VERSION 5.7 ;
  NOWIREEXTENSIONATPIN ON ;
  DIVIDERCHAR "/" ;
  BUSBITCHARS "[]" ;
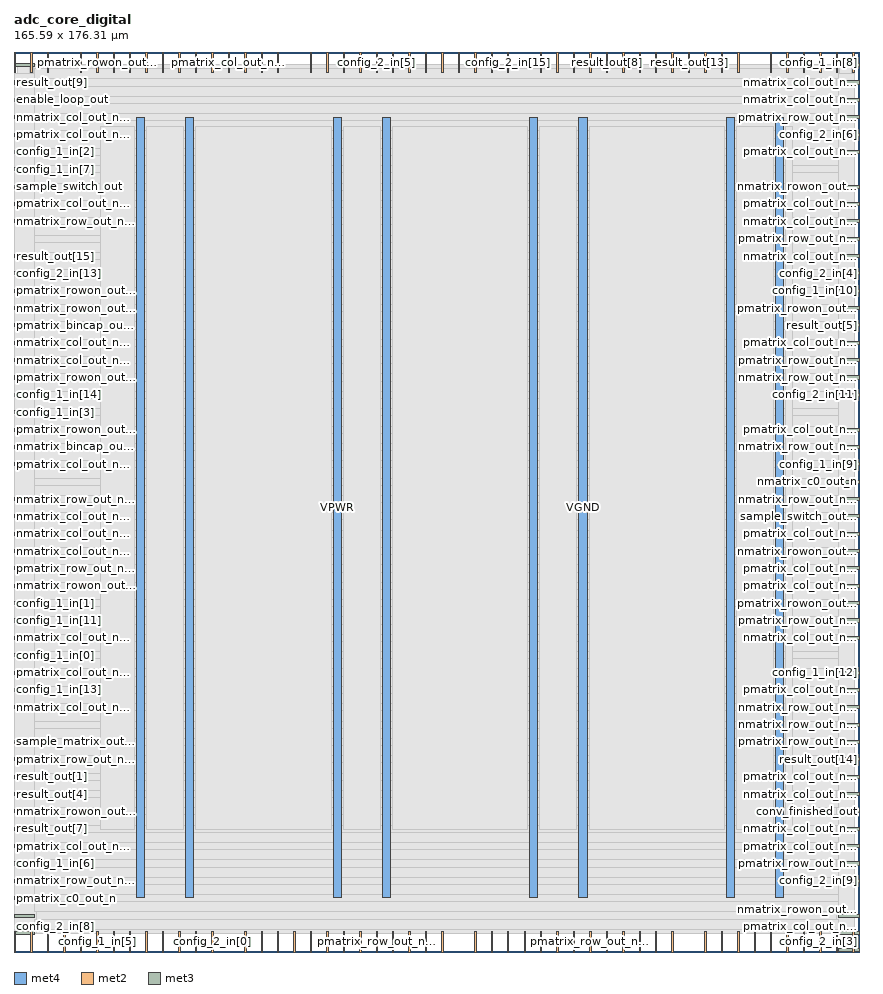
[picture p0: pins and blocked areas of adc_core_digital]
MACRO adc_core_digital
  CLASS BLOCK ;
  FOREIGN adc_core_digital ;
  ORIGIN 0.000 0.000 ;
  SIZE 165.590 BY 176.310 ;
  PIN VGND
    DIRECTION INOUT ;
    USE GROUND ;
    PORT
      LAYER met4 ;
        RECT 33.610 10.640 35.210 163.440 ;
    END
    PORT
      LAYER met4 ;
        RECT 72.135 10.640 73.735 163.440 ;
    END
    PORT
      LAYER met4 ;
        RECT 110.660 10.640 112.260 163.440 ;
    END
    PORT
      LAYER met4 ;
        RECT 149.185 10.640 150.785 163.440 ;
    END
  END VGND
  PIN VPWR
    DIRECTION INOUT ;
    USE POWER ;
    PORT
      LAYER met4 ;
        RECT 23.980 10.640 25.580 163.440 ;
    END
    PORT
      LAYER met4 ;
        RECT 62.505 10.640 64.105 163.440 ;
    END
    PORT
      LAYER met4 ;
        RECT 101.030 10.640 102.630 163.440 ;
    END
    PORT
      LAYER met4 ;
        RECT 139.555 10.640 141.155 163.440 ;
    END
  END VPWR
  PIN clk_dig_in
    DIRECTION INPUT ;
    USE SIGNAL ;
    PORT
      LAYER met2 ;
        RECT 135.330 172.310 135.610 176.310 ;
    END
  END clk_dig_in
  PIN comparator_in
    DIRECTION INPUT ;
    USE SIGNAL ;
    PORT
      LAYER met2 ;
        RECT 51.610 172.310 51.890 176.310 ;
    END
  END comparator_in
  PIN config_1_in[0]
    DIRECTION INPUT ;
    USE SIGNAL ;
    PORT
      LAYER met3 ;
        RECT 0.000 57.840 4.000 58.440 ;
    END
  END config_1_in[0]
  PIN config_1_in[10]
    DIRECTION INPUT ;
    USE SIGNAL ;
    PORT
      LAYER met3 ;
        RECT 161.590 129.240 165.590 129.840 ;
    END
  END config_1_in[10]
  PIN config_1_in[11]
    DIRECTION INPUT ;
    USE SIGNAL ;
    PORT
      LAYER met3 ;
        RECT 0.000 64.640 4.000 65.240 ;
    END
  END config_1_in[11]
  PIN config_1_in[12]
    DIRECTION INPUT ;
    USE SIGNAL ;
    PORT
      LAYER met3 ;
        RECT 161.590 54.440 165.590 55.040 ;
    END
  END config_1_in[12]
  PIN config_1_in[13]
    DIRECTION INPUT ;
    USE SIGNAL ;
    PORT
      LAYER met3 ;
        RECT 0.000 51.040 4.000 51.640 ;
    END
  END config_1_in[13]
  PIN config_1_in[14]
    DIRECTION INPUT ;
    USE SIGNAL ;
    PORT
      LAYER met3 ;
        RECT 0.000 108.840 4.000 109.440 ;
    END
  END config_1_in[14]
  PIN config_1_in[15]
    DIRECTION INPUT ;
    USE SIGNAL ;
    PORT
      LAYER met2 ;
        RECT 35.510 172.310 35.790 176.310 ;
    END
  END config_1_in[15]
  PIN config_1_in[1]
    DIRECTION INPUT ;
    USE SIGNAL ;
    PORT
      LAYER met3 ;
        RECT 0.000 68.040 4.000 68.640 ;
    END
  END config_1_in[1]
  PIN config_1_in[2]
    DIRECTION INPUT ;
    USE SIGNAL ;
    PORT
      LAYER met3 ;
        RECT 0.000 156.440 4.000 157.040 ;
    END
  END config_1_in[2]
  PIN config_1_in[3]
    DIRECTION INPUT ;
    USE SIGNAL ;
    PORT
      LAYER met3 ;
        RECT 0.000 105.440 4.000 106.040 ;
    END
  END config_1_in[3]
  PIN config_1_in[4]
    DIRECTION INPUT ;
    USE SIGNAL ;
    PORT
      LAYER met2 ;
        RECT 29.070 172.310 29.350 176.310 ;
    END
  END config_1_in[4]
  PIN config_1_in[5]
    DIRECTION INPUT ;
    USE SIGNAL ;
    PORT
      LAYER met2 ;
        RECT 16.190 0.000 16.470 4.000 ;
    END
  END config_1_in[5]
  PIN config_1_in[6]
    DIRECTION INPUT ;
    USE SIGNAL ;
    PORT
      LAYER met3 ;
        RECT 0.000 17.040 4.000 17.640 ;
    END
  END config_1_in[6]
  PIN config_1_in[7]
    DIRECTION INPUT ;
    USE SIGNAL ;
    PORT
      LAYER met3 ;
        RECT 0.000 153.040 4.000 153.640 ;
    END
  END config_1_in[7]
  PIN config_1_in[8]
    DIRECTION INPUT ;
    USE SIGNAL ;
    PORT
      LAYER met2 ;
        RECT 161.090 172.310 161.370 176.310 ;
    END
  END config_1_in[8]
  PIN config_1_in[9]
    DIRECTION INPUT ;
    USE SIGNAL ;
    PORT
      LAYER met3 ;
        RECT 161.590 95.240 165.590 95.840 ;
    END
  END config_1_in[9]
  PIN config_2_in[0]
    DIRECTION INPUT ;
    USE SIGNAL ;
    PORT
      LAYER met2 ;
        RECT 38.730 0.000 39.010 4.000 ;
    END
  END config_2_in[0]
  PIN config_2_in[10]
    DIRECTION INPUT ;
    USE SIGNAL ;
    PORT
      LAYER met2 ;
        RECT 67.710 172.310 67.990 176.310 ;
    END
  END config_2_in[10]
  PIN config_2_in[11]
    DIRECTION INPUT ;
    USE SIGNAL ;
    PORT
      LAYER met3 ;
        RECT 161.590 108.840 165.590 109.440 ;
    END
  END config_2_in[11]
  PIN config_2_in[12]
    DIRECTION INPUT ;
    USE SIGNAL ;
    PORT
      LAYER met3 ;
        RECT 161.590 0.040 165.590 0.640 ;
    END
  END config_2_in[12]
  PIN config_2_in[13]
    DIRECTION INPUT ;
    USE SIGNAL ;
    PORT
      LAYER met3 ;
        RECT 0.000 132.640 4.000 133.240 ;
    END
  END config_2_in[13]
  PIN config_2_in[14]
    DIRECTION INPUT ;
    USE SIGNAL ;
    PORT
      LAYER met2 ;
        RECT 54.830 0.000 55.110 4.000 ;
    END
  END config_2_in[14]
  PIN config_2_in[15]
    DIRECTION INPUT ;
    USE SIGNAL ;
    PORT
      LAYER met2 ;
        RECT 96.690 172.310 96.970 176.310 ;
    END
  END config_2_in[15]
  PIN config_2_in[1]
    DIRECTION INPUT ;
    USE SIGNAL ;
    PORT
      LAYER met2 ;
        RECT 109.570 0.000 109.850 4.000 ;
    END
  END config_2_in[1]
  PIN config_2_in[2]
    DIRECTION INPUT ;
    USE SIGNAL ;
    PORT
      LAYER met2 ;
        RECT 87.030 172.310 87.310 176.310 ;
    END
  END config_2_in[2]
  PIN config_2_in[3]
    DIRECTION INPUT ;
    USE SIGNAL ;
    PORT
      LAYER met2 ;
        RECT 157.870 0.000 158.150 4.000 ;
    END
  END config_2_in[3]
  PIN config_2_in[4]
    DIRECTION INPUT ;
    USE SIGNAL ;
    PORT
      LAYER met3 ;
        RECT 161.590 132.640 165.590 133.240 ;
    END
  END config_2_in[4]
  PIN config_2_in[5]
    DIRECTION INPUT ;
    USE SIGNAL ;
    PORT
      LAYER met2 ;
        RECT 70.930 172.310 71.210 176.310 ;
    END
  END config_2_in[5]
  PIN config_2_in[6]
    DIRECTION INPUT ;
    USE SIGNAL ;
    PORT
      LAYER met3 ;
        RECT 161.590 159.840 165.590 160.440 ;
    END
  END config_2_in[6]
  PIN config_2_in[7]
    DIRECTION INPUT ;
    USE SIGNAL ;
    PORT
      LAYER met2 ;
        RECT 138.550 172.310 138.830 176.310 ;
    END
  END config_2_in[7]
  PIN config_2_in[8]
    DIRECTION INPUT ;
    USE SIGNAL ;
    PORT
      LAYER met3 ;
        RECT 0.000 3.440 4.000 4.040 ;
    END
  END config_2_in[8]
  PIN config_2_in[9]
    DIRECTION INPUT ;
    USE SIGNAL ;
    PORT
      LAYER met3 ;
        RECT 161.590 13.640 165.590 14.240 ;
    END
  END config_2_in[9]
  PIN conv_finished_out
    DIRECTION OUTPUT TRISTATE ;
    USE SIGNAL ;
    PORT
      LAYER met3 ;
        RECT 161.590 27.240 165.590 27.840 ;
    END
  END conv_finished_out
  PIN enable_loop_out
    DIRECTION OUTPUT TRISTATE ;
    USE SIGNAL ;
    PORT
      LAYER met3 ;
        RECT 0.000 166.640 4.000 167.240 ;
    END
  END enable_loop_out
  PIN nmatrix_bincap_out_n[0]
    DIRECTION OUTPUT TRISTATE ;
    USE SIGNAL ;
    PORT
      LAYER met2 ;
        RECT 6.530 172.310 6.810 176.310 ;
    END
  END nmatrix_bincap_out_n[0]
  PIN nmatrix_bincap_out_n[1]
    DIRECTION OUTPUT TRISTATE ;
    USE SIGNAL ;
    PORT
      LAYER met3 ;
        RECT 0.000 98.640 4.000 99.240 ;
    END
  END nmatrix_bincap_out_n[1]
  PIN nmatrix_bincap_out_n[2]
    DIRECTION OUTPUT TRISTATE ;
    USE SIGNAL ;
    PORT
      LAYER met3 ;
        RECT 0.000 6.840 4.000 7.440 ;
    END
  END nmatrix_bincap_out_n[2]
  PIN nmatrix_c0_out_n
    DIRECTION OUTPUT TRISTATE ;
    USE SIGNAL ;
    PORT
      LAYER met3 ;
        RECT 161.590 91.840 165.590 92.440 ;
    END
  END nmatrix_c0_out_n
  PIN nmatrix_col_out_n[0]
    DIRECTION OUTPUT TRISTATE ;
    USE SIGNAL ;
    PORT
      LAYER met3 ;
        RECT 0.000 85.040 4.000 85.640 ;
    END
  END nmatrix_col_out_n[0]
  PIN nmatrix_col_out_n[10]
    DIRECTION OUTPUT TRISTATE ;
    USE SIGNAL ;
    PORT
      LAYER met3 ;
        RECT 0.000 173.440 4.000 174.040 ;
    END
  END nmatrix_col_out_n[10]
  PIN nmatrix_col_out_n[11]
    DIRECTION OUTPUT TRISTATE ;
    USE SIGNAL ;
    PORT
      LAYER met3 ;
        RECT 0.000 163.240 4.000 163.840 ;
    END
  END nmatrix_col_out_n[11]
  PIN nmatrix_col_out_n[12]
    DIRECTION OUTPUT TRISTATE ;
    USE SIGNAL ;
    PORT
      LAYER met2 ;
        RECT 151.430 0.000 151.710 4.000 ;
    END
  END nmatrix_col_out_n[12]
  PIN nmatrix_col_out_n[13]
    DIRECTION OUTPUT TRISTATE ;
    USE SIGNAL ;
    PORT
      LAYER met3 ;
        RECT 0.000 115.640 4.000 116.240 ;
    END
  END nmatrix_col_out_n[13]
  PIN nmatrix_col_out_n[14]
    DIRECTION OUTPUT TRISTATE ;
    USE SIGNAL ;
    PORT
      LAYER met2 ;
        RECT 148.210 172.310 148.490 176.310 ;
    END
  END nmatrix_col_out_n[14]
  PIN nmatrix_col_out_n[15]
    DIRECTION OUTPUT TRISTATE ;
    USE SIGNAL ;
    PORT
      LAYER met3 ;
        RECT 161.590 61.240 165.590 61.840 ;
    END
  END nmatrix_col_out_n[15]
  PIN nmatrix_col_out_n[16]
    DIRECTION OUTPUT TRISTATE ;
    USE SIGNAL ;
    PORT
      LAYER met3 ;
        RECT 0.000 119.040 4.000 119.640 ;
    END
  END nmatrix_col_out_n[16]
  PIN nmatrix_col_out_n[17]
    DIRECTION OUTPUT TRISTATE ;
    USE SIGNAL ;
    PORT
      LAYER met3 ;
        RECT 161.590 23.840 165.590 24.440 ;
    END
  END nmatrix_col_out_n[17]
  PIN nmatrix_col_out_n[18]
    DIRECTION OUTPUT TRISTATE ;
    USE SIGNAL ;
    PORT
      LAYER met2 ;
        RECT 48.390 0.000 48.670 4.000 ;
    END
  END nmatrix_col_out_n[18]
  PIN nmatrix_col_out_n[19]
    DIRECTION OUTPUT TRISTATE ;
    USE SIGNAL ;
    PORT
      LAYER met3 ;
        RECT 0.000 47.640 4.000 48.240 ;
    END
  END nmatrix_col_out_n[19]
  PIN nmatrix_col_out_n[1]
    DIRECTION OUTPUT TRISTATE ;
    USE SIGNAL ;
    PORT
      LAYER met3 ;
        RECT 0.000 61.240 4.000 61.840 ;
    END
  END nmatrix_col_out_n[1]
  PIN nmatrix_col_out_n[20]
    DIRECTION OUTPUT TRISTATE ;
    USE SIGNAL ;
    PORT
      LAYER met3 ;
        RECT 161.590 136.040 165.590 136.640 ;
    END
  END nmatrix_col_out_n[20]
  PIN nmatrix_col_out_n[21]
    DIRECTION OUTPUT TRISTATE ;
    USE SIGNAL ;
    PORT
      LAYER met2 ;
        RECT 48.390 172.310 48.670 176.310 ;
    END
  END nmatrix_col_out_n[21]
  PIN nmatrix_col_out_n[22]
    DIRECTION OUTPUT TRISTATE ;
    USE SIGNAL ;
    PORT
      LAYER met3 ;
        RECT 161.590 170.040 165.590 170.640 ;
    END
  END nmatrix_col_out_n[22]
  PIN nmatrix_col_out_n[23]
    DIRECTION OUTPUT TRISTATE ;
    USE SIGNAL ;
    PORT
      LAYER met3 ;
        RECT 0.000 81.640 4.000 82.240 ;
    END
  END nmatrix_col_out_n[23]
  PIN nmatrix_col_out_n[24]
    DIRECTION OUTPUT TRISTATE ;
    USE SIGNAL ;
    PORT
      LAYER met2 ;
        RECT 12.970 0.000 13.250 4.000 ;
    END
  END nmatrix_col_out_n[24]
  PIN nmatrix_col_out_n[25]
    DIRECTION OUTPUT TRISTATE ;
    USE SIGNAL ;
    PORT
      LAYER met3 ;
        RECT 0.000 78.240 4.000 78.840 ;
    END
  END nmatrix_col_out_n[25]
  PIN nmatrix_col_out_n[26]
    DIRECTION OUTPUT TRISTATE ;
    USE SIGNAL ;
    PORT
      LAYER met2 ;
        RECT 80.590 172.310 80.870 176.310 ;
    END
  END nmatrix_col_out_n[26]
  PIN nmatrix_col_out_n[27]
    DIRECTION OUTPUT TRISTATE ;
    USE SIGNAL ;
    PORT
      LAYER met3 ;
        RECT 161.590 142.840 165.590 143.440 ;
    END
  END nmatrix_col_out_n[27]
  PIN nmatrix_col_out_n[28]
    DIRECTION OUTPUT TRISTATE ;
    USE SIGNAL ;
    PORT
      LAYER met2 ;
        RECT 58.050 172.310 58.330 176.310 ;
    END
  END nmatrix_col_out_n[28]
  PIN nmatrix_col_out_n[29]
    DIRECTION OUTPUT TRISTATE ;
    USE SIGNAL ;
    PORT
      LAYER met3 ;
        RECT 161.590 166.640 165.590 167.240 ;
    END
  END nmatrix_col_out_n[29]
  PIN nmatrix_col_out_n[2]
    DIRECTION OUTPUT TRISTATE ;
    USE SIGNAL ;
    PORT
      LAYER met2 ;
        RECT 12.970 172.310 13.250 176.310 ;
    END
  END nmatrix_col_out_n[2]
  PIN nmatrix_col_out_n[30]
    DIRECTION OUTPUT TRISTATE ;
    USE SIGNAL ;
    PORT
      LAYER met2 ;
        RECT 128.890 0.000 129.170 4.000 ;
    END
  END nmatrix_col_out_n[30]
  PIN nmatrix_col_out_n[31]
    DIRECTION OUTPUT TRISTATE ;
    USE SIGNAL ;
    PORT
      LAYER met2 ;
        RECT 141.770 172.310 142.050 176.310 ;
    END
  END nmatrix_col_out_n[31]
  PIN nmatrix_col_out_n[3]
    DIRECTION OUTPUT TRISTATE ;
    USE SIGNAL ;
    PORT
      LAYER met2 ;
        RECT 25.850 172.310 26.130 176.310 ;
    END
  END nmatrix_col_out_n[3]
  PIN nmatrix_col_out_n[4]
    DIRECTION OUTPUT TRISTATE ;
    USE SIGNAL ;
    PORT
      LAYER met2 ;
        RECT 77.370 0.000 77.650 4.000 ;
    END
  END nmatrix_col_out_n[4]
  PIN nmatrix_col_out_n[5]
    DIRECTION OUTPUT TRISTATE ;
    USE SIGNAL ;
    PORT
      LAYER met2 ;
        RECT 135.330 0.000 135.610 4.000 ;
    END
  END nmatrix_col_out_n[5]
  PIN nmatrix_col_out_n[6]
    DIRECTION OUTPUT TRISTATE ;
    USE SIGNAL ;
    PORT
      LAYER met3 ;
        RECT 161.590 30.640 165.590 31.240 ;
    END
  END nmatrix_col_out_n[6]
  PIN nmatrix_col_out_n[7]
    DIRECTION OUTPUT TRISTATE ;
    USE SIGNAL ;
    PORT
      LAYER met2 ;
        RECT 125.670 0.000 125.950 4.000 ;
    END
  END nmatrix_col_out_n[7]
  PIN nmatrix_col_out_n[8]
    DIRECTION OUTPUT TRISTATE ;
    USE SIGNAL ;
    PORT
      LAYER met2 ;
        RECT 64.490 0.000 64.770 4.000 ;
    END
  END nmatrix_col_out_n[8]
  PIN nmatrix_col_out_n[9]
    DIRECTION OUTPUT TRISTATE ;
    USE SIGNAL ;
    PORT
      LAYER met3 ;
        RECT 161.590 173.440 165.590 174.040 ;
    END
  END nmatrix_col_out_n[9]
  PIN nmatrix_row_out_n[0]
    DIRECTION OUTPUT TRISTATE ;
    USE SIGNAL ;
    PORT
      LAYER met3 ;
        RECT 0.000 88.440 4.000 89.040 ;
    END
  END nmatrix_row_out_n[0]
  PIN nmatrix_row_out_n[10]
    DIRECTION OUTPUT TRISTATE ;
    USE SIGNAL ;
    PORT
      LAYER met3 ;
        RECT 161.590 47.640 165.590 48.240 ;
    END
  END nmatrix_row_out_n[10]
  PIN nmatrix_row_out_n[11]
    DIRECTION OUTPUT TRISTATE ;
    USE SIGNAL ;
    PORT
      LAYER met2 ;
        RECT 80.590 0.000 80.870 4.000 ;
    END
  END nmatrix_row_out_n[11]
  PIN nmatrix_row_out_n[12]
    DIRECTION OUTPUT TRISTATE ;
    USE SIGNAL ;
    PORT
      LAYER met3 ;
        RECT 161.590 88.440 165.590 89.040 ;
    END
  END nmatrix_row_out_n[12]
  PIN nmatrix_row_out_n[13]
    DIRECTION OUTPUT TRISTATE ;
    USE SIGNAL ;
    PORT
      LAYER met2 ;
        RECT 125.670 172.310 125.950 176.310 ;
    END
  END nmatrix_row_out_n[13]
  PIN nmatrix_row_out_n[14]
    DIRECTION OUTPUT TRISTATE ;
    USE SIGNAL ;
    PORT
      LAYER met2 ;
        RECT 45.170 172.310 45.450 176.310 ;
    END
  END nmatrix_row_out_n[14]
  PIN nmatrix_row_out_n[15]
    DIRECTION OUTPUT TRISTATE ;
    USE SIGNAL ;
    PORT
      LAYER met2 ;
        RECT 51.610 0.000 51.890 4.000 ;
    END
  END nmatrix_row_out_n[15]
  PIN nmatrix_row_out_n[1]
    DIRECTION OUTPUT TRISTATE ;
    USE SIGNAL ;
    PORT
      LAYER met3 ;
        RECT 0.000 142.840 4.000 143.440 ;
    END
  END nmatrix_row_out_n[1]
  PIN nmatrix_row_out_n[2]
    DIRECTION OUTPUT TRISTATE ;
    USE SIGNAL ;
    PORT
      LAYER met2 ;
        RECT 22.630 0.000 22.910 4.000 ;
    END
  END nmatrix_row_out_n[2]
  PIN nmatrix_row_out_n[3]
    DIRECTION OUTPUT TRISTATE ;
    USE SIGNAL ;
    PORT
      LAYER met2 ;
        RECT 90.250 0.000 90.530 4.000 ;
    END
  END nmatrix_row_out_n[3]
  PIN nmatrix_row_out_n[4]
    DIRECTION OUTPUT TRISTATE ;
    USE SIGNAL ;
    PORT
      LAYER met3 ;
        RECT 161.590 98.640 165.590 99.240 ;
    END
  END nmatrix_row_out_n[4]
  PIN nmatrix_row_out_n[5]
    DIRECTION OUTPUT TRISTATE ;
    USE SIGNAL ;
    PORT
      LAYER met3 ;
        RECT 161.590 44.240 165.590 44.840 ;
    END
  END nmatrix_row_out_n[5]
  PIN nmatrix_row_out_n[6]
    DIRECTION OUTPUT TRISTATE ;
    USE SIGNAL ;
    PORT
      LAYER met2 ;
        RECT 106.350 172.310 106.630 176.310 ;
    END
  END nmatrix_row_out_n[6]
  PIN nmatrix_row_out_n[7]
    DIRECTION OUTPUT TRISTATE ;
    USE SIGNAL ;
    PORT
      LAYER met3 ;
        RECT 161.590 112.240 165.590 112.840 ;
    END
  END nmatrix_row_out_n[7]
  PIN nmatrix_row_out_n[8]
    DIRECTION OUTPUT TRISTATE ;
    USE SIGNAL ;
    PORT
      LAYER met2 ;
        RECT 122.450 172.310 122.730 176.310 ;
    END
  END nmatrix_row_out_n[8]
  PIN nmatrix_row_out_n[9]
    DIRECTION OUTPUT TRISTATE ;
    USE SIGNAL ;
    PORT
      LAYER met3 ;
        RECT 0.000 13.640 4.000 14.240 ;
    END
  END nmatrix_row_out_n[9]
  PIN nmatrix_rowon_out_n[0]
    DIRECTION OUTPUT TRISTATE ;
    USE SIGNAL ;
    PORT
      LAYER met3 ;
        RECT 0.000 125.840 4.000 126.440 ;
    END
  END nmatrix_rowon_out_n[0]
  PIN nmatrix_rowon_out_n[10]
    DIRECTION OUTPUT TRISTATE ;
    USE SIGNAL ;
    PORT
      LAYER met2 ;
        RECT 138.550 0.000 138.830 4.000 ;
    END
  END nmatrix_rowon_out_n[10]
  PIN nmatrix_rowon_out_n[11]
    DIRECTION OUTPUT TRISTATE ;
    USE SIGNAL ;
    PORT
      LAYER met3 ;
        RECT 161.590 78.240 165.590 78.840 ;
    END
  END nmatrix_rowon_out_n[11]
  PIN nmatrix_rowon_out_n[12]
    DIRECTION OUTPUT TRISTATE ;
    USE SIGNAL ;
    PORT
      LAYER met2 ;
        RECT 151.430 172.310 151.710 176.310 ;
    END
  END nmatrix_rowon_out_n[12]
  PIN nmatrix_rowon_out_n[13]
    DIRECTION OUTPUT TRISTATE ;
    USE SIGNAL ;
    PORT
      LAYER met3 ;
        RECT 161.590 149.640 165.590 150.240 ;
    END
  END nmatrix_rowon_out_n[13]
  PIN nmatrix_rowon_out_n[14]
    DIRECTION OUTPUT TRISTATE ;
    USE SIGNAL ;
    PORT
      LAYER met2 ;
        RECT 6.530 0.000 6.810 4.000 ;
    END
  END nmatrix_rowon_out_n[14]
  PIN nmatrix_rowon_out_n[15]
    DIRECTION OUTPUT TRISTATE ;
    USE SIGNAL ;
    PORT
      LAYER met2 ;
        RECT 58.050 0.000 58.330 4.000 ;
    END
  END nmatrix_rowon_out_n[15]
  PIN nmatrix_rowon_out_n[1]
    DIRECTION OUTPUT TRISTATE ;
    USE SIGNAL ;
    PORT
      LAYER met2 ;
        RECT 119.230 172.310 119.510 176.310 ;
    END
  END nmatrix_rowon_out_n[1]
  PIN nmatrix_rowon_out_n[2]
    DIRECTION OUTPUT TRISTATE ;
    USE SIGNAL ;
    PORT
      LAYER met2 ;
        RECT 19.410 172.310 19.690 176.310 ;
    END
  END nmatrix_rowon_out_n[2]
  PIN nmatrix_rowon_out_n[3]
    DIRECTION OUTPUT TRISTATE ;
    USE SIGNAL ;
    PORT
      LAYER met2 ;
        RECT 67.710 0.000 67.990 4.000 ;
    END
  END nmatrix_rowon_out_n[3]
  PIN nmatrix_rowon_out_n[4]
    DIRECTION OUTPUT TRISTATE ;
    USE SIGNAL ;
    PORT
      LAYER met3 ;
        RECT 161.590 6.840 165.590 7.440 ;
    END
  END nmatrix_rowon_out_n[4]
  PIN nmatrix_rowon_out_n[5]
    DIRECTION OUTPUT TRISTATE ;
    USE SIGNAL ;
    PORT
      LAYER met2 ;
        RECT 144.990 0.000 145.270 4.000 ;
    END
  END nmatrix_rowon_out_n[5]
  PIN nmatrix_rowon_out_n[6]
    DIRECTION OUTPUT TRISTATE ;
    USE SIGNAL ;
    PORT
      LAYER met2 ;
        RECT 106.350 0.000 106.630 4.000 ;
    END
  END nmatrix_rowon_out_n[6]
  PIN nmatrix_rowon_out_n[7]
    DIRECTION OUTPUT TRISTATE ;
    USE SIGNAL ;
    PORT
      LAYER met3 ;
        RECT 0.000 71.440 4.000 72.040 ;
    END
  END nmatrix_rowon_out_n[7]
  PIN nmatrix_rowon_out_n[8]
    DIRECTION OUTPUT TRISTATE ;
    USE SIGNAL ;
    PORT
      LAYER met3 ;
        RECT 0.000 27.240 4.000 27.840 ;
    END
  END nmatrix_rowon_out_n[8]
  PIN nmatrix_rowon_out_n[9]
    DIRECTION OUTPUT TRISTATE ;
    USE SIGNAL ;
    PORT
      LAYER met2 ;
        RECT 128.890 172.310 129.170 176.310 ;
    END
  END nmatrix_rowon_out_n[9]
  PIN pmatrix_bincap_out_n[0]
    DIRECTION OUTPUT TRISTATE ;
    USE SIGNAL ;
    PORT
      LAYER met2 ;
        RECT 38.730 172.310 39.010 176.310 ;
    END
  END pmatrix_bincap_out_n[0]
  PIN pmatrix_bincap_out_n[1]
    DIRECTION OUTPUT TRISTATE ;
    USE SIGNAL ;
    PORT
      LAYER met2 ;
        RECT 141.770 0.000 142.050 4.000 ;
    END
  END pmatrix_bincap_out_n[1]
  PIN pmatrix_bincap_out_n[2]
    DIRECTION OUTPUT TRISTATE ;
    USE SIGNAL ;
    PORT
      LAYER met3 ;
        RECT 0.000 122.440 4.000 123.040 ;
    END
  END pmatrix_bincap_out_n[2]
  PIN pmatrix_c0_out_n
    DIRECTION OUTPUT TRISTATE ;
    USE SIGNAL ;
    PORT
      LAYER met3 ;
        RECT 0.000 10.240 4.000 10.840 ;
    END
  END pmatrix_c0_out_n
  PIN pmatrix_col_out_n[0]
    DIRECTION OUTPUT TRISTATE ;
    USE SIGNAL ;
    PORT
      LAYER met3 ;
        RECT 0.000 54.440 4.000 55.040 ;
    END
  END pmatrix_col_out_n[0]
  PIN pmatrix_col_out_n[10]
    DIRECTION OUTPUT TRISTATE ;
    USE SIGNAL ;
    PORT
      LAYER met3 ;
        RECT 161.590 156.440 165.590 157.040 ;
    END
  END pmatrix_col_out_n[10]
  PIN pmatrix_col_out_n[11]
    DIRECTION OUTPUT TRISTATE ;
    USE SIGNAL ;
    PORT
      LAYER met3 ;
        RECT 161.590 20.440 165.590 21.040 ;
    END
  END pmatrix_col_out_n[11]
  PIN pmatrix_col_out_n[12]
    DIRECTION OUTPUT TRISTATE ;
    USE SIGNAL ;
    PORT
      LAYER met3 ;
        RECT 161.590 71.440 165.590 72.040 ;
    END
  END pmatrix_col_out_n[12]
  PIN pmatrix_col_out_n[13]
    DIRECTION OUTPUT TRISTATE ;
    USE SIGNAL ;
    PORT
      LAYER met2 ;
        RECT 3.310 172.310 3.590 176.310 ;
    END
  END pmatrix_col_out_n[13]
  PIN pmatrix_col_out_n[14]
    DIRECTION OUTPUT TRISTATE ;
    USE SIGNAL ;
    PORT
      LAYER met3 ;
        RECT 161.590 102.040 165.590 102.640 ;
    END
  END pmatrix_col_out_n[14]
  PIN pmatrix_col_out_n[15]
    DIRECTION OUTPUT TRISTATE ;
    USE SIGNAL ;
    PORT
      LAYER met3 ;
        RECT 161.590 3.440 165.590 4.040 ;
    END
  END pmatrix_col_out_n[15]
  PIN pmatrix_col_out_n[16]
    DIRECTION OUTPUT TRISTATE ;
    USE SIGNAL ;
    PORT
      LAYER met2 ;
        RECT 93.470 172.310 93.750 176.310 ;
    END
  END pmatrix_col_out_n[16]
  PIN pmatrix_col_out_n[17]
    DIRECTION OUTPUT TRISTATE ;
    USE SIGNAL ;
    PORT
      LAYER met2 ;
        RECT 41.950 172.310 42.230 176.310 ;
    END
  END pmatrix_col_out_n[17]
  PIN pmatrix_col_out_n[18]
    DIRECTION OUTPUT TRISTATE ;
    USE SIGNAL ;
    PORT
      LAYER met2 ;
        RECT 93.470 0.000 93.750 4.000 ;
    END
  END pmatrix_col_out_n[18]
  PIN pmatrix_col_out_n[19]
    DIRECTION OUTPUT TRISTATE ;
    USE SIGNAL ;
    PORT
      LAYER met2 ;
        RECT 35.510 0.000 35.790 4.000 ;
    END
  END pmatrix_col_out_n[19]
  PIN pmatrix_col_out_n[1]
    DIRECTION OUTPUT TRISTATE ;
    USE SIGNAL ;
    PORT
      LAYER met2 ;
        RECT 61.270 172.310 61.550 176.310 ;
    END
  END pmatrix_col_out_n[1]
  PIN pmatrix_col_out_n[20]
    DIRECTION OUTPUT TRISTATE ;
    USE SIGNAL ;
    PORT
      LAYER met2 ;
        RECT 122.450 0.000 122.730 4.000 ;
    END
  END pmatrix_col_out_n[20]
  PIN pmatrix_col_out_n[21]
    DIRECTION OUTPUT TRISTATE ;
    USE SIGNAL ;
    PORT
      LAYER met2 ;
        RECT 161.090 0.000 161.370 4.000 ;
    END
  END pmatrix_col_out_n[21]
  PIN pmatrix_col_out_n[22]
    DIRECTION OUTPUT TRISTATE ;
    USE SIGNAL ;
    PORT
      LAYER met2 ;
        RECT 157.870 172.310 158.150 176.310 ;
    END
  END pmatrix_col_out_n[22]
  PIN pmatrix_col_out_n[23]
    DIRECTION OUTPUT TRISTATE ;
    USE SIGNAL ;
    PORT
      LAYER met3 ;
        RECT 161.590 74.840 165.590 75.440 ;
    END
  END pmatrix_col_out_n[23]
  PIN pmatrix_col_out_n[24]
    DIRECTION OUTPUT TRISTATE ;
    USE SIGNAL ;
    PORT
      LAYER met2 ;
        RECT 64.490 172.310 64.770 176.310 ;
    END
  END pmatrix_col_out_n[24]
  PIN pmatrix_col_out_n[25]
    DIRECTION OUTPUT TRISTATE ;
    USE SIGNAL ;
    PORT
      LAYER met2 ;
        RECT 90.250 172.310 90.530 176.310 ;
    END
  END pmatrix_col_out_n[25]
  PIN pmatrix_col_out_n[26]
    DIRECTION OUTPUT TRISTATE ;
    USE SIGNAL ;
    PORT
      LAYER met2 ;
        RECT 83.810 172.310 84.090 176.310 ;
    END
  END pmatrix_col_out_n[26]
  PIN pmatrix_col_out_n[27]
    DIRECTION OUTPUT TRISTATE ;
    USE SIGNAL ;
    PORT
      LAYER met3 ;
        RECT 0.000 95.240 4.000 95.840 ;
    END
  END pmatrix_col_out_n[27]
  PIN pmatrix_col_out_n[28]
    DIRECTION OUTPUT TRISTATE ;
    USE SIGNAL ;
    PORT
      LAYER met2 ;
        RECT 25.850 0.000 26.130 4.000 ;
    END
  END pmatrix_col_out_n[28]
  PIN pmatrix_col_out_n[29]
    DIRECTION OUTPUT TRISTATE ;
    USE SIGNAL ;
    PORT
      LAYER met3 ;
        RECT 161.590 34.040 165.590 34.640 ;
    END
  END pmatrix_col_out_n[29]
  PIN pmatrix_col_out_n[2]
    DIRECTION OUTPUT TRISTATE ;
    USE SIGNAL ;
    PORT
      LAYER met2 ;
        RECT 74.150 0.000 74.430 4.000 ;
    END
  END pmatrix_col_out_n[2]
  PIN pmatrix_col_out_n[30]
    DIRECTION OUTPUT TRISTATE ;
    USE SIGNAL ;
    PORT
      LAYER met3 ;
        RECT 161.590 146.240 165.590 146.840 ;
    END
  END pmatrix_col_out_n[30]
  PIN pmatrix_col_out_n[31]
    DIRECTION OUTPUT TRISTATE ;
    USE SIGNAL ;
    PORT
      LAYER met3 ;
        RECT 0.000 146.240 4.000 146.840 ;
    END
  END pmatrix_col_out_n[31]
  PIN pmatrix_col_out_n[3]
    DIRECTION OUTPUT TRISTATE ;
    USE SIGNAL ;
    PORT
      LAYER met2 ;
        RECT 103.130 172.310 103.410 176.310 ;
    END
  END pmatrix_col_out_n[3]
  PIN pmatrix_col_out_n[4]
    DIRECTION OUTPUT TRISTATE ;
    USE SIGNAL ;
    PORT
      LAYER met3 ;
        RECT 0.000 159.840 4.000 160.440 ;
    END
  END pmatrix_col_out_n[4]
  PIN pmatrix_col_out_n[5]
    DIRECTION OUTPUT TRISTATE ;
    USE SIGNAL ;
    PORT
      LAYER met3 ;
        RECT 161.590 51.040 165.590 51.640 ;
    END
  END pmatrix_col_out_n[5]
  PIN pmatrix_col_out_n[6]
    DIRECTION OUTPUT TRISTATE ;
    USE SIGNAL ;
    PORT
      LAYER met3 ;
        RECT 161.590 119.040 165.590 119.640 ;
    END
  END pmatrix_col_out_n[6]
  PIN pmatrix_col_out_n[7]
    DIRECTION OUTPUT TRISTATE ;
    USE SIGNAL ;
    PORT
      LAYER met2 ;
        RECT 32.290 172.310 32.570 176.310 ;
    END
  END pmatrix_col_out_n[7]
  PIN pmatrix_col_out_n[8]
    DIRECTION OUTPUT TRISTATE ;
    USE SIGNAL ;
    PORT
      LAYER met3 ;
        RECT 161.590 81.640 165.590 82.240 ;
    END
  END pmatrix_col_out_n[8]
  PIN pmatrix_col_out_n[9]
    DIRECTION OUTPUT TRISTATE ;
    USE SIGNAL ;
    PORT
      LAYER met3 ;
        RECT 0.000 20.440 4.000 21.040 ;
    END
  END pmatrix_col_out_n[9]
  PIN pmatrix_row_out_n[0]
    DIRECTION OUTPUT TRISTATE ;
    USE SIGNAL ;
    PORT
      LAYER met3 ;
        RECT 0.000 37.440 4.000 38.040 ;
    END
  END pmatrix_row_out_n[0]
  PIN pmatrix_row_out_n[10]
    DIRECTION OUTPUT TRISTATE ;
    USE SIGNAL ;
    PORT
      LAYER met3 ;
        RECT 161.590 139.440 165.590 140.040 ;
    END
  END pmatrix_row_out_n[10]
  PIN pmatrix_row_out_n[11]
    DIRECTION OUTPUT TRISTATE ;
    USE SIGNAL ;
    PORT
      LAYER met2 ;
        RECT 112.790 172.310 113.070 176.310 ;
    END
  END pmatrix_row_out_n[11]
  PIN pmatrix_row_out_n[12]
    DIRECTION OUTPUT TRISTATE ;
    USE SIGNAL ;
    PORT
      LAYER met2 ;
        RECT 45.170 0.000 45.450 4.000 ;
    END
  END pmatrix_row_out_n[12]
  PIN pmatrix_row_out_n[13]
    DIRECTION OUTPUT TRISTATE ;
    USE SIGNAL ;
    PORT
      LAYER met3 ;
        RECT 161.590 64.640 165.590 65.240 ;
    END
  END pmatrix_row_out_n[13]
  PIN pmatrix_row_out_n[14]
    DIRECTION OUTPUT TRISTATE ;
    USE SIGNAL ;
    PORT
      LAYER met2 ;
        RECT 112.790 0.000 113.070 4.000 ;
    END
  END pmatrix_row_out_n[14]
  PIN pmatrix_row_out_n[15]
    DIRECTION OUTPUT TRISTATE ;
    USE SIGNAL ;
    PORT
      LAYER met3 ;
        RECT 161.590 17.040 165.590 17.640 ;
    END
  END pmatrix_row_out_n[15]
  PIN pmatrix_row_out_n[1]
    DIRECTION OUTPUT TRISTATE ;
    USE SIGNAL ;
    PORT
      LAYER met2 ;
        RECT 0.090 172.310 0.370 176.310 ;
    END
  END pmatrix_row_out_n[1]
  PIN pmatrix_row_out_n[2]
    DIRECTION OUTPUT TRISTATE ;
    USE SIGNAL ;
    PORT
      LAYER met2 ;
        RECT 148.210 0.000 148.490 4.000 ;
    END
  END pmatrix_row_out_n[2]
  PIN pmatrix_row_out_n[3]
    DIRECTION OUTPUT TRISTATE ;
    USE SIGNAL ;
    PORT
      LAYER met2 ;
        RECT 19.410 0.000 19.690 4.000 ;
    END
  END pmatrix_row_out_n[3]
  PIN pmatrix_row_out_n[4]
    DIRECTION OUTPUT TRISTATE ;
    USE SIGNAL ;
    PORT
      LAYER met2 ;
        RECT 70.930 0.000 71.210 4.000 ;
    END
  END pmatrix_row_out_n[4]
  PIN pmatrix_row_out_n[5]
    DIRECTION OUTPUT TRISTATE ;
    USE SIGNAL ;
    PORT
      LAYER met3 ;
        RECT 161.590 40.840 165.590 41.440 ;
    END
  END pmatrix_row_out_n[5]
  PIN pmatrix_row_out_n[6]
    DIRECTION OUTPUT TRISTATE ;
    USE SIGNAL ;
    PORT
      LAYER met3 ;
        RECT 161.590 163.240 165.590 163.840 ;
    END
  END pmatrix_row_out_n[6]
  PIN pmatrix_row_out_n[7]
    DIRECTION OUTPUT TRISTATE ;
    USE SIGNAL ;
    PORT
      LAYER met3 ;
        RECT 161.590 115.640 165.590 116.240 ;
    END
  END pmatrix_row_out_n[7]
  PIN pmatrix_row_out_n[8]
    DIRECTION OUTPUT TRISTATE ;
    USE SIGNAL ;
    PORT
      LAYER met2 ;
        RECT 154.650 0.000 154.930 4.000 ;
    END
  END pmatrix_row_out_n[8]
  PIN pmatrix_row_out_n[9]
    DIRECTION OUTPUT TRISTATE ;
    USE SIGNAL ;
    PORT
      LAYER met3 ;
        RECT 0.000 74.840 4.000 75.440 ;
    END
  END pmatrix_row_out_n[9]
  PIN pmatrix_rowon_out_n[0]
    DIRECTION OUTPUT TRISTATE ;
    USE SIGNAL ;
    PORT
      LAYER met3 ;
        RECT 161.590 68.040 165.590 68.640 ;
    END
  END pmatrix_rowon_out_n[0]
  PIN pmatrix_rowon_out_n[10]
    DIRECTION OUTPUT TRISTATE ;
    USE SIGNAL ;
    PORT
      LAYER met2 ;
        RECT 3.310 0.000 3.590 4.000 ;
    END
  END pmatrix_rowon_out_n[10]
  PIN pmatrix_rowon_out_n[11]
    DIRECTION OUTPUT TRISTATE ;
    USE SIGNAL ;
    PORT
      LAYER met3 ;
        RECT 161.590 125.840 165.590 126.440 ;
    END
  END pmatrix_rowon_out_n[11]
  PIN pmatrix_rowon_out_n[12]
    DIRECTION OUTPUT TRISTATE ;
    USE SIGNAL ;
    PORT
      LAYER met2 ;
        RECT 164.310 172.310 164.590 176.310 ;
    END
  END pmatrix_rowon_out_n[12]
  PIN pmatrix_rowon_out_n[13]
    DIRECTION OUTPUT TRISTATE ;
    USE SIGNAL ;
    PORT
      LAYER met2 ;
        RECT 164.310 0.000 164.590 4.000 ;
    END
  END pmatrix_rowon_out_n[13]
  PIN pmatrix_rowon_out_n[14]
    DIRECTION OUTPUT TRISTATE ;
    USE SIGNAL ;
    PORT
      LAYER met2 ;
        RECT 154.650 172.310 154.930 176.310 ;
    END
  END pmatrix_rowon_out_n[14]
  PIN pmatrix_rowon_out_n[15]
    DIRECTION OUTPUT TRISTATE ;
    USE SIGNAL ;
    PORT
      LAYER met2 ;
        RECT 99.910 0.000 100.190 4.000 ;
    END
  END pmatrix_rowon_out_n[15]
  PIN pmatrix_rowon_out_n[1]
    DIRECTION OUTPUT TRISTATE ;
    USE SIGNAL ;
    PORT
      LAYER met3 ;
        RECT 0.000 112.240 4.000 112.840 ;
    END
  END pmatrix_rowon_out_n[1]
  PIN pmatrix_rowon_out_n[2]
    DIRECTION OUTPUT TRISTATE ;
    USE SIGNAL ;
    PORT
      LAYER met2 ;
        RECT 103.130 0.000 103.410 4.000 ;
    END
  END pmatrix_rowon_out_n[2]
  PIN pmatrix_rowon_out_n[3]
    DIRECTION OUTPUT TRISTATE ;
    USE SIGNAL ;
    PORT
      LAYER met2 ;
        RECT 0.090 0.000 0.370 4.000 ;
    END
  END pmatrix_rowon_out_n[3]
  PIN pmatrix_rowon_out_n[4]
    DIRECTION OUTPUT TRISTATE ;
    USE SIGNAL ;
    PORT
      LAYER met2 ;
        RECT 119.230 0.000 119.510 4.000 ;
    END
  END pmatrix_rowon_out_n[4]
  PIN pmatrix_rowon_out_n[5]
    DIRECTION OUTPUT TRISTATE ;
    USE SIGNAL ;
    PORT
      LAYER met3 ;
        RECT 0.000 129.240 4.000 129.840 ;
    END
  END pmatrix_rowon_out_n[5]
  PIN pmatrix_rowon_out_n[6]
    DIRECTION OUTPUT TRISTATE ;
    USE SIGNAL ;
    PORT
      LAYER met2 ;
        RECT 16.190 172.310 16.470 176.310 ;
    END
  END pmatrix_rowon_out_n[6]
  PIN pmatrix_rowon_out_n[7]
    DIRECTION OUTPUT TRISTATE ;
    USE SIGNAL ;
    PORT
      LAYER met2 ;
        RECT 77.370 172.310 77.650 176.310 ;
    END
  END pmatrix_rowon_out_n[7]
  PIN pmatrix_rowon_out_n[8]
    DIRECTION OUTPUT TRISTATE ;
    USE SIGNAL ;
    PORT
      LAYER met3 ;
        RECT 0.000 102.040 4.000 102.640 ;
    END
  END pmatrix_rowon_out_n[8]
  PIN pmatrix_rowon_out_n[9]
    DIRECTION OUTPUT TRISTATE ;
    USE SIGNAL ;
    PORT
      LAYER met2 ;
        RECT 29.070 0.000 29.350 4.000 ;
    END
  END pmatrix_rowon_out_n[9]
  PIN result_out[0]
    DIRECTION OUTPUT TRISTATE ;
    USE SIGNAL ;
    PORT
      LAYER met2 ;
        RECT 9.750 0.000 10.030 4.000 ;
    END
  END result_out[0]
  PIN result_out[10]
    DIRECTION OUTPUT TRISTATE ;
    USE SIGNAL ;
    PORT
      LAYER met2 ;
        RECT 109.570 172.310 109.850 176.310 ;
    END
  END result_out[10]
  PIN result_out[11]
    DIRECTION OUTPUT TRISTATE ;
    USE SIGNAL ;
    PORT
      LAYER met2 ;
        RECT 74.150 172.310 74.430 176.310 ;
    END
  END result_out[11]
  PIN result_out[12]
    DIRECTION OUTPUT TRISTATE ;
    USE SIGNAL ;
    PORT
      LAYER met2 ;
        RECT 83.810 0.000 84.090 4.000 ;
    END
  END result_out[12]
  PIN result_out[13]
    DIRECTION OUTPUT TRISTATE ;
    USE SIGNAL ;
    PORT
      LAYER met2 ;
        RECT 132.110 172.310 132.390 176.310 ;
    END
  END result_out[13]
  PIN result_out[14]
    DIRECTION OUTPUT TRISTATE ;
    USE SIGNAL ;
    PORT
      LAYER met3 ;
        RECT 161.590 37.440 165.590 38.040 ;
    END
  END result_out[14]
  PIN result_out[15]
    DIRECTION OUTPUT TRISTATE ;
    USE SIGNAL ;
    PORT
      LAYER met3 ;
        RECT 0.000 136.040 4.000 136.640 ;
    END
  END result_out[15]
  PIN result_out[1]
    DIRECTION OUTPUT TRISTATE ;
    USE SIGNAL ;
    PORT
      LAYER met3 ;
        RECT 0.000 34.040 4.000 34.640 ;
    END
  END result_out[1]
  PIN result_out[2]
    DIRECTION OUTPUT TRISTATE ;
    USE SIGNAL ;
    PORT
      LAYER met2 ;
        RECT 32.290 0.000 32.570 4.000 ;
    END
  END result_out[2]
  PIN result_out[3]
    DIRECTION OUTPUT TRISTATE ;
    USE SIGNAL ;
    PORT
      LAYER met2 ;
        RECT 61.270 0.000 61.550 4.000 ;
    END
  END result_out[3]
  PIN result_out[4]
    DIRECTION OUTPUT TRISTATE ;
    USE SIGNAL ;
    PORT
      LAYER met3 ;
        RECT 0.000 30.640 4.000 31.240 ;
    END
  END result_out[4]
  PIN result_out[5]
    DIRECTION OUTPUT TRISTATE ;
    USE SIGNAL ;
    PORT
      LAYER met3 ;
        RECT 161.590 122.440 165.590 123.040 ;
    END
  END result_out[5]
  PIN result_out[6]
    DIRECTION OUTPUT TRISTATE ;
    USE SIGNAL ;
    PORT
      LAYER met2 ;
        RECT 96.690 0.000 96.970 4.000 ;
    END
  END result_out[6]
  PIN result_out[7]
    DIRECTION OUTPUT TRISTATE ;
    USE SIGNAL ;
    PORT
      LAYER met3 ;
        RECT 0.000 23.840 4.000 24.440 ;
    END
  END result_out[7]
  PIN result_out[8]
    DIRECTION OUTPUT TRISTATE ;
    USE SIGNAL ;
    PORT
      LAYER met2 ;
        RECT 116.010 172.310 116.290 176.310 ;
    END
  END result_out[8]
  PIN result_out[9]
    DIRECTION OUTPUT TRISTATE ;
    USE SIGNAL ;
    PORT
      LAYER met3 ;
        RECT 0.000 170.040 4.000 170.640 ;
    END
  END result_out[9]
  PIN rst_n
    DIRECTION INPUT ;
    USE SIGNAL ;
    PORT
      LAYER met2 ;
        RECT 22.630 172.310 22.910 176.310 ;
    END
  END rst_n
  PIN sample_matrix_out
    DIRECTION OUTPUT TRISTATE ;
    USE SIGNAL ;
    PORT
      LAYER met2 ;
        RECT 116.010 0.000 116.290 4.000 ;
    END
  END sample_matrix_out
  PIN sample_matrix_out_n
    DIRECTION OUTPUT TRISTATE ;
    USE SIGNAL ;
    PORT
      LAYER met3 ;
        RECT 0.000 40.840 4.000 41.440 ;
    END
  END sample_matrix_out_n
  PIN sample_switch_out
    DIRECTION OUTPUT TRISTATE ;
    USE SIGNAL ;
    PORT
      LAYER met3 ;
        RECT 0.000 149.640 4.000 150.240 ;
    END
  END sample_switch_out
  PIN sample_switch_out_n
    DIRECTION OUTPUT TRISTATE ;
    USE SIGNAL ;
    PORT
      LAYER met3 ;
        RECT 161.590 85.040 165.590 85.640 ;
    END
  END sample_switch_out_n
  OBS
      LAYER li1 ;
        RECT 5.520 10.795 159.620 163.285 ;
      LAYER met1 ;
        RECT 0.070 6.500 164.610 165.880 ;
      LAYER met2 ;
        RECT 0.650 172.030 3.030 173.925 ;
        RECT 3.870 172.030 6.250 173.925 ;
        RECT 7.090 172.030 12.690 173.925 ;
        RECT 13.530 172.030 15.910 173.925 ;
        RECT 16.750 172.030 19.130 173.925 ;
        RECT 19.970 172.030 22.350 173.925 ;
        RECT 23.190 172.030 25.570 173.925 ;
        RECT 26.410 172.030 28.790 173.925 ;
        RECT 29.630 172.030 32.010 173.925 ;
        RECT 32.850 172.030 35.230 173.925 ;
        RECT 36.070 172.030 38.450 173.925 ;
        RECT 39.290 172.030 41.670 173.925 ;
        RECT 42.510 172.030 44.890 173.925 ;
        RECT 45.730 172.030 48.110 173.925 ;
        RECT 48.950 172.030 51.330 173.925 ;
        RECT 52.170 172.030 57.770 173.925 ;
        RECT 58.610 172.030 60.990 173.925 ;
        RECT 61.830 172.030 64.210 173.925 ;
        RECT 65.050 172.030 67.430 173.925 ;
        RECT 68.270 172.030 70.650 173.925 ;
        RECT 71.490 172.030 73.870 173.925 ;
        RECT 74.710 172.030 77.090 173.925 ;
        RECT 77.930 172.030 80.310 173.925 ;
        RECT 81.150 172.030 83.530 173.925 ;
        RECT 84.370 172.030 86.750 173.925 ;
        RECT 87.590 172.030 89.970 173.925 ;
        RECT 90.810 172.030 93.190 173.925 ;
        RECT 94.030 172.030 96.410 173.925 ;
        RECT 97.250 172.030 102.850 173.925 ;
        RECT 103.690 172.030 106.070 173.925 ;
        RECT 106.910 172.030 109.290 173.925 ;
        RECT 110.130 172.030 112.510 173.925 ;
        RECT 113.350 172.030 115.730 173.925 ;
        RECT 116.570 172.030 118.950 173.925 ;
        RECT 119.790 172.030 122.170 173.925 ;
        RECT 123.010 172.030 125.390 173.925 ;
        RECT 126.230 172.030 128.610 173.925 ;
        RECT 129.450 172.030 131.830 173.925 ;
        RECT 132.670 172.030 135.050 173.925 ;
        RECT 135.890 172.030 138.270 173.925 ;
        RECT 139.110 172.030 141.490 173.925 ;
        RECT 142.330 172.030 147.930 173.925 ;
        RECT 148.770 172.030 151.150 173.925 ;
        RECT 151.990 172.030 154.370 173.925 ;
        RECT 155.210 172.030 157.590 173.925 ;
        RECT 158.430 172.030 160.810 173.925 ;
        RECT 161.650 172.030 164.030 173.925 ;
        RECT 0.100 4.280 164.580 172.030 ;
        RECT 0.650 3.555 3.030 4.280 ;
        RECT 3.870 3.555 6.250 4.280 ;
        RECT 7.090 3.555 9.470 4.280 ;
        RECT 10.310 3.555 12.690 4.280 ;
        RECT 13.530 3.555 15.910 4.280 ;
        RECT 16.750 3.555 19.130 4.280 ;
        RECT 19.970 3.555 22.350 4.280 ;
        RECT 23.190 3.555 25.570 4.280 ;
        RECT 26.410 3.555 28.790 4.280 ;
        RECT 29.630 3.555 32.010 4.280 ;
        RECT 32.850 3.555 35.230 4.280 ;
        RECT 36.070 3.555 38.450 4.280 ;
        RECT 39.290 3.555 44.890 4.280 ;
        RECT 45.730 3.555 48.110 4.280 ;
        RECT 48.950 3.555 51.330 4.280 ;
        RECT 52.170 3.555 54.550 4.280 ;
        RECT 55.390 3.555 57.770 4.280 ;
        RECT 58.610 3.555 60.990 4.280 ;
        RECT 61.830 3.555 64.210 4.280 ;
        RECT 65.050 3.555 67.430 4.280 ;
        RECT 68.270 3.555 70.650 4.280 ;
        RECT 71.490 3.555 73.870 4.280 ;
        RECT 74.710 3.555 77.090 4.280 ;
        RECT 77.930 3.555 80.310 4.280 ;
        RECT 81.150 3.555 83.530 4.280 ;
        RECT 84.370 3.555 89.970 4.280 ;
        RECT 90.810 3.555 93.190 4.280 ;
        RECT 94.030 3.555 96.410 4.280 ;
        RECT 97.250 3.555 99.630 4.280 ;
        RECT 100.470 3.555 102.850 4.280 ;
        RECT 103.690 3.555 106.070 4.280 ;
        RECT 106.910 3.555 109.290 4.280 ;
        RECT 110.130 3.555 112.510 4.280 ;
        RECT 113.350 3.555 115.730 4.280 ;
        RECT 116.570 3.555 118.950 4.280 ;
        RECT 119.790 3.555 122.170 4.280 ;
        RECT 123.010 3.555 125.390 4.280 ;
        RECT 126.230 3.555 128.610 4.280 ;
        RECT 129.450 3.555 135.050 4.280 ;
        RECT 135.890 3.555 138.270 4.280 ;
        RECT 139.110 3.555 141.490 4.280 ;
        RECT 142.330 3.555 144.710 4.280 ;
        RECT 145.550 3.555 147.930 4.280 ;
        RECT 148.770 3.555 151.150 4.280 ;
        RECT 151.990 3.555 154.370 4.280 ;
        RECT 155.210 3.555 157.590 4.280 ;
        RECT 158.430 3.555 160.810 4.280 ;
        RECT 161.650 3.555 164.030 4.280 ;
      LAYER met3 ;
        RECT 4.400 173.040 161.190 173.905 ;
        RECT 4.000 171.040 161.590 173.040 ;
        RECT 4.400 169.640 161.190 171.040 ;
        RECT 4.000 167.640 161.590 169.640 ;
        RECT 4.400 166.240 161.190 167.640 ;
        RECT 4.000 164.240 161.590 166.240 ;
        RECT 4.400 162.840 161.190 164.240 ;
        RECT 4.000 160.840 161.590 162.840 ;
        RECT 4.400 159.440 161.190 160.840 ;
        RECT 4.000 157.440 161.590 159.440 ;
        RECT 4.400 156.040 161.190 157.440 ;
        RECT 4.000 154.040 161.590 156.040 ;
        RECT 4.400 152.640 161.590 154.040 ;
        RECT 4.000 150.640 161.590 152.640 ;
        RECT 4.400 149.240 161.190 150.640 ;
        RECT 4.000 147.240 161.590 149.240 ;
        RECT 4.400 145.840 161.190 147.240 ;
        RECT 4.000 143.840 161.590 145.840 ;
        RECT 4.400 142.440 161.190 143.840 ;
        RECT 4.000 140.440 161.590 142.440 ;
        RECT 4.000 139.040 161.190 140.440 ;
        RECT 4.000 137.040 161.590 139.040 ;
        RECT 4.400 135.640 161.190 137.040 ;
        RECT 4.000 133.640 161.590 135.640 ;
        RECT 4.400 132.240 161.190 133.640 ;
        RECT 4.000 130.240 161.590 132.240 ;
        RECT 4.400 128.840 161.190 130.240 ;
        RECT 4.000 126.840 161.590 128.840 ;
        RECT 4.400 125.440 161.190 126.840 ;
        RECT 4.000 123.440 161.590 125.440 ;
        RECT 4.400 122.040 161.190 123.440 ;
        RECT 4.000 120.040 161.590 122.040 ;
        RECT 4.400 118.640 161.190 120.040 ;
        RECT 4.000 116.640 161.590 118.640 ;
        RECT 4.400 115.240 161.190 116.640 ;
        RECT 4.000 113.240 161.590 115.240 ;
        RECT 4.400 111.840 161.190 113.240 ;
        RECT 4.000 109.840 161.590 111.840 ;
        RECT 4.400 108.440 161.190 109.840 ;
        RECT 4.000 106.440 161.590 108.440 ;
        RECT 4.400 105.040 161.590 106.440 ;
        RECT 4.000 103.040 161.590 105.040 ;
        RECT 4.400 101.640 161.190 103.040 ;
        RECT 4.000 99.640 161.590 101.640 ;
        RECT 4.400 98.240 161.190 99.640 ;
        RECT 4.000 96.240 161.590 98.240 ;
        RECT 4.400 94.840 161.190 96.240 ;
        RECT 4.000 92.840 161.590 94.840 ;
        RECT 4.000 91.440 161.190 92.840 ;
        RECT 4.000 89.440 161.590 91.440 ;
        RECT 4.400 88.040 161.190 89.440 ;
        RECT 4.000 86.040 161.590 88.040 ;
        RECT 4.400 84.640 161.190 86.040 ;
        RECT 4.000 82.640 161.590 84.640 ;
        RECT 4.400 81.240 161.190 82.640 ;
        RECT 4.000 79.240 161.590 81.240 ;
        RECT 4.400 77.840 161.190 79.240 ;
        RECT 4.000 75.840 161.590 77.840 ;
        RECT 4.400 74.440 161.190 75.840 ;
        RECT 4.000 72.440 161.590 74.440 ;
        RECT 4.400 71.040 161.190 72.440 ;
        RECT 4.000 69.040 161.590 71.040 ;
        RECT 4.400 67.640 161.190 69.040 ;
        RECT 4.000 65.640 161.590 67.640 ;
        RECT 4.400 64.240 161.190 65.640 ;
        RECT 4.000 62.240 161.590 64.240 ;
        RECT 4.400 60.840 161.190 62.240 ;
        RECT 4.000 58.840 161.590 60.840 ;
        RECT 4.400 57.440 161.590 58.840 ;
        RECT 4.000 55.440 161.590 57.440 ;
        RECT 4.400 54.040 161.190 55.440 ;
        RECT 4.000 52.040 161.590 54.040 ;
        RECT 4.400 50.640 161.190 52.040 ;
        RECT 4.000 48.640 161.590 50.640 ;
        RECT 4.400 47.240 161.190 48.640 ;
        RECT 4.000 45.240 161.590 47.240 ;
        RECT 4.000 43.840 161.190 45.240 ;
        RECT 4.000 41.840 161.590 43.840 ;
        RECT 4.400 40.440 161.190 41.840 ;
        RECT 4.000 38.440 161.590 40.440 ;
        RECT 4.400 37.040 161.190 38.440 ;
        RECT 4.000 35.040 161.590 37.040 ;
        RECT 4.400 33.640 161.190 35.040 ;
        RECT 4.000 31.640 161.590 33.640 ;
        RECT 4.400 30.240 161.190 31.640 ;
        RECT 4.000 28.240 161.590 30.240 ;
        RECT 4.400 26.840 161.190 28.240 ;
        RECT 4.000 24.840 161.590 26.840 ;
        RECT 4.400 23.440 161.190 24.840 ;
        RECT 4.000 21.440 161.590 23.440 ;
        RECT 4.400 20.040 161.190 21.440 ;
        RECT 4.000 18.040 161.590 20.040 ;
        RECT 4.400 16.640 161.190 18.040 ;
        RECT 4.000 14.640 161.590 16.640 ;
        RECT 4.400 13.240 161.190 14.640 ;
        RECT 4.000 11.240 161.590 13.240 ;
        RECT 4.400 9.840 161.590 11.240 ;
        RECT 4.000 7.840 161.590 9.840 ;
        RECT 4.400 6.440 161.190 7.840 ;
        RECT 4.000 4.440 161.590 6.440 ;
        RECT 4.400 3.575 161.190 4.440 ;
      LAYER met4 ;
        RECT 16.855 23.975 23.580 161.665 ;
        RECT 25.980 23.975 33.210 161.665 ;
        RECT 35.610 23.975 62.105 161.665 ;
        RECT 64.505 23.975 71.735 161.665 ;
        RECT 74.135 23.975 100.630 161.665 ;
        RECT 103.030 23.975 110.260 161.665 ;
        RECT 112.660 23.975 139.155 161.665 ;
        RECT 141.555 23.975 148.785 161.665 ;
        RECT 151.185 23.975 152.425 161.665 ;
  END
END adc_core_digital
END LIBRARY

